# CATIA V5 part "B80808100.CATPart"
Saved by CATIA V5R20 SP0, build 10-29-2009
Part number: B80808100
Revision: 4
Definition: design
Nomenclature: B80808100
Source: made
Description: NOT SPECIFIED
Bounding box of the stored display mesh (mm): x -5.85 to 5.85, y -6 to 6, z 0 to 100
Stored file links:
  C:\Users\Raffaele\Desktop\3D X SITO CF\BOLEX\4-PILLAR REF 808\B80808100.CATPart

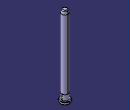
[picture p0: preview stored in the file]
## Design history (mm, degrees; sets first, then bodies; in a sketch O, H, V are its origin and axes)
Body1 "MANIFOLD_SOLID_BREP #450" (main body)
  Solid1: solid without history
